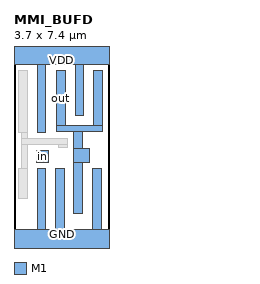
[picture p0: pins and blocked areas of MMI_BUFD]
MACRO MMI_BUFD
	CLASS CORE ;
	FOREIGN MMI_BUFD 0 0 ;
	SIZE 3.7 BY 7.4 ;
	SYMMETRY X Y ;
	SITE CORE1 ;
	PIN out
		DIRECTION output ;
		USE SIGNAL ;
		PORT
			LAYER M1 ;
			RECT 1.66 4.525 2 6.67 ;
			LAYER M1 ;
			RECT 3.1 4.525 3.44 6.67 ;
			LAYER M1 ;
			RECT 1.66 4.295 3.44 4.525 ;
			LAYER M1 ;
			RECT 2.33 3.64 2.67 4.295 ;
			LAYER M1 ;
			RECT 2.33 3.09 2.925 3.64 ;
			LAYER M1 ;
			RECT 2.33 1.1 2.67 3.09 ;
		END
		AntennaDiffArea 3.4977 ;
	END out
	PIN GND
		DIRECTION inout ;
		USE GROUND ;
		PORT
			LAYER M1 ;
			RECT 0.9 0.5 1.24 2.86 ;
			LAYER M1 ;
			RECT 1.61 0.5 1.95 2.86 ;
			LAYER M1 ;
			RECT 3.05 0.5 3.39 2.86 ;
			LAYER M1 ;
			RECT 0 -0.5 3.7 0.5 ;
		END
	END GND
	PIN VDD
		DIRECTION inout ;
		USE POWER ;
		PORT
			LAYER M1 ;
			RECT 0 6.9 3.7 7.9 ;
			LAYER M1 ;
			RECT 0.9 4.27 1.24 6.9 ;
			LAYER M1 ;
			RECT 2.38 4.915 2.72 6.9 ;
		END
	END VDD
	PIN in
		DIRECTION input ;
		USE SIGNAL ;
		PORT
			LAYER M1 ;
			RECT 0.885 3.105 1.335 3.555 ;
		END
		AntennaGateArea 0.6696 ;
	END in
	OBS
		LAYER M1 ;
		RECT 0.18 4.27 0.52 6.67 ;
		LAYER M1 ;
		RECT 0.29 4.025 0.52 4.27 ;
		LAYER M1 ;
		RECT 0.29 3.795 2.09 4.025 ;
		LAYER M1 ;
		RECT 0.29 2.86 0.52 3.795 ;
		LAYER M1 ;
		RECT 1.75 3.685 2.09 3.795 ;
		LAYER M1 ;
		RECT 0.18 1.7 0.52 2.86 ;
	END
END MMI_BUFD
